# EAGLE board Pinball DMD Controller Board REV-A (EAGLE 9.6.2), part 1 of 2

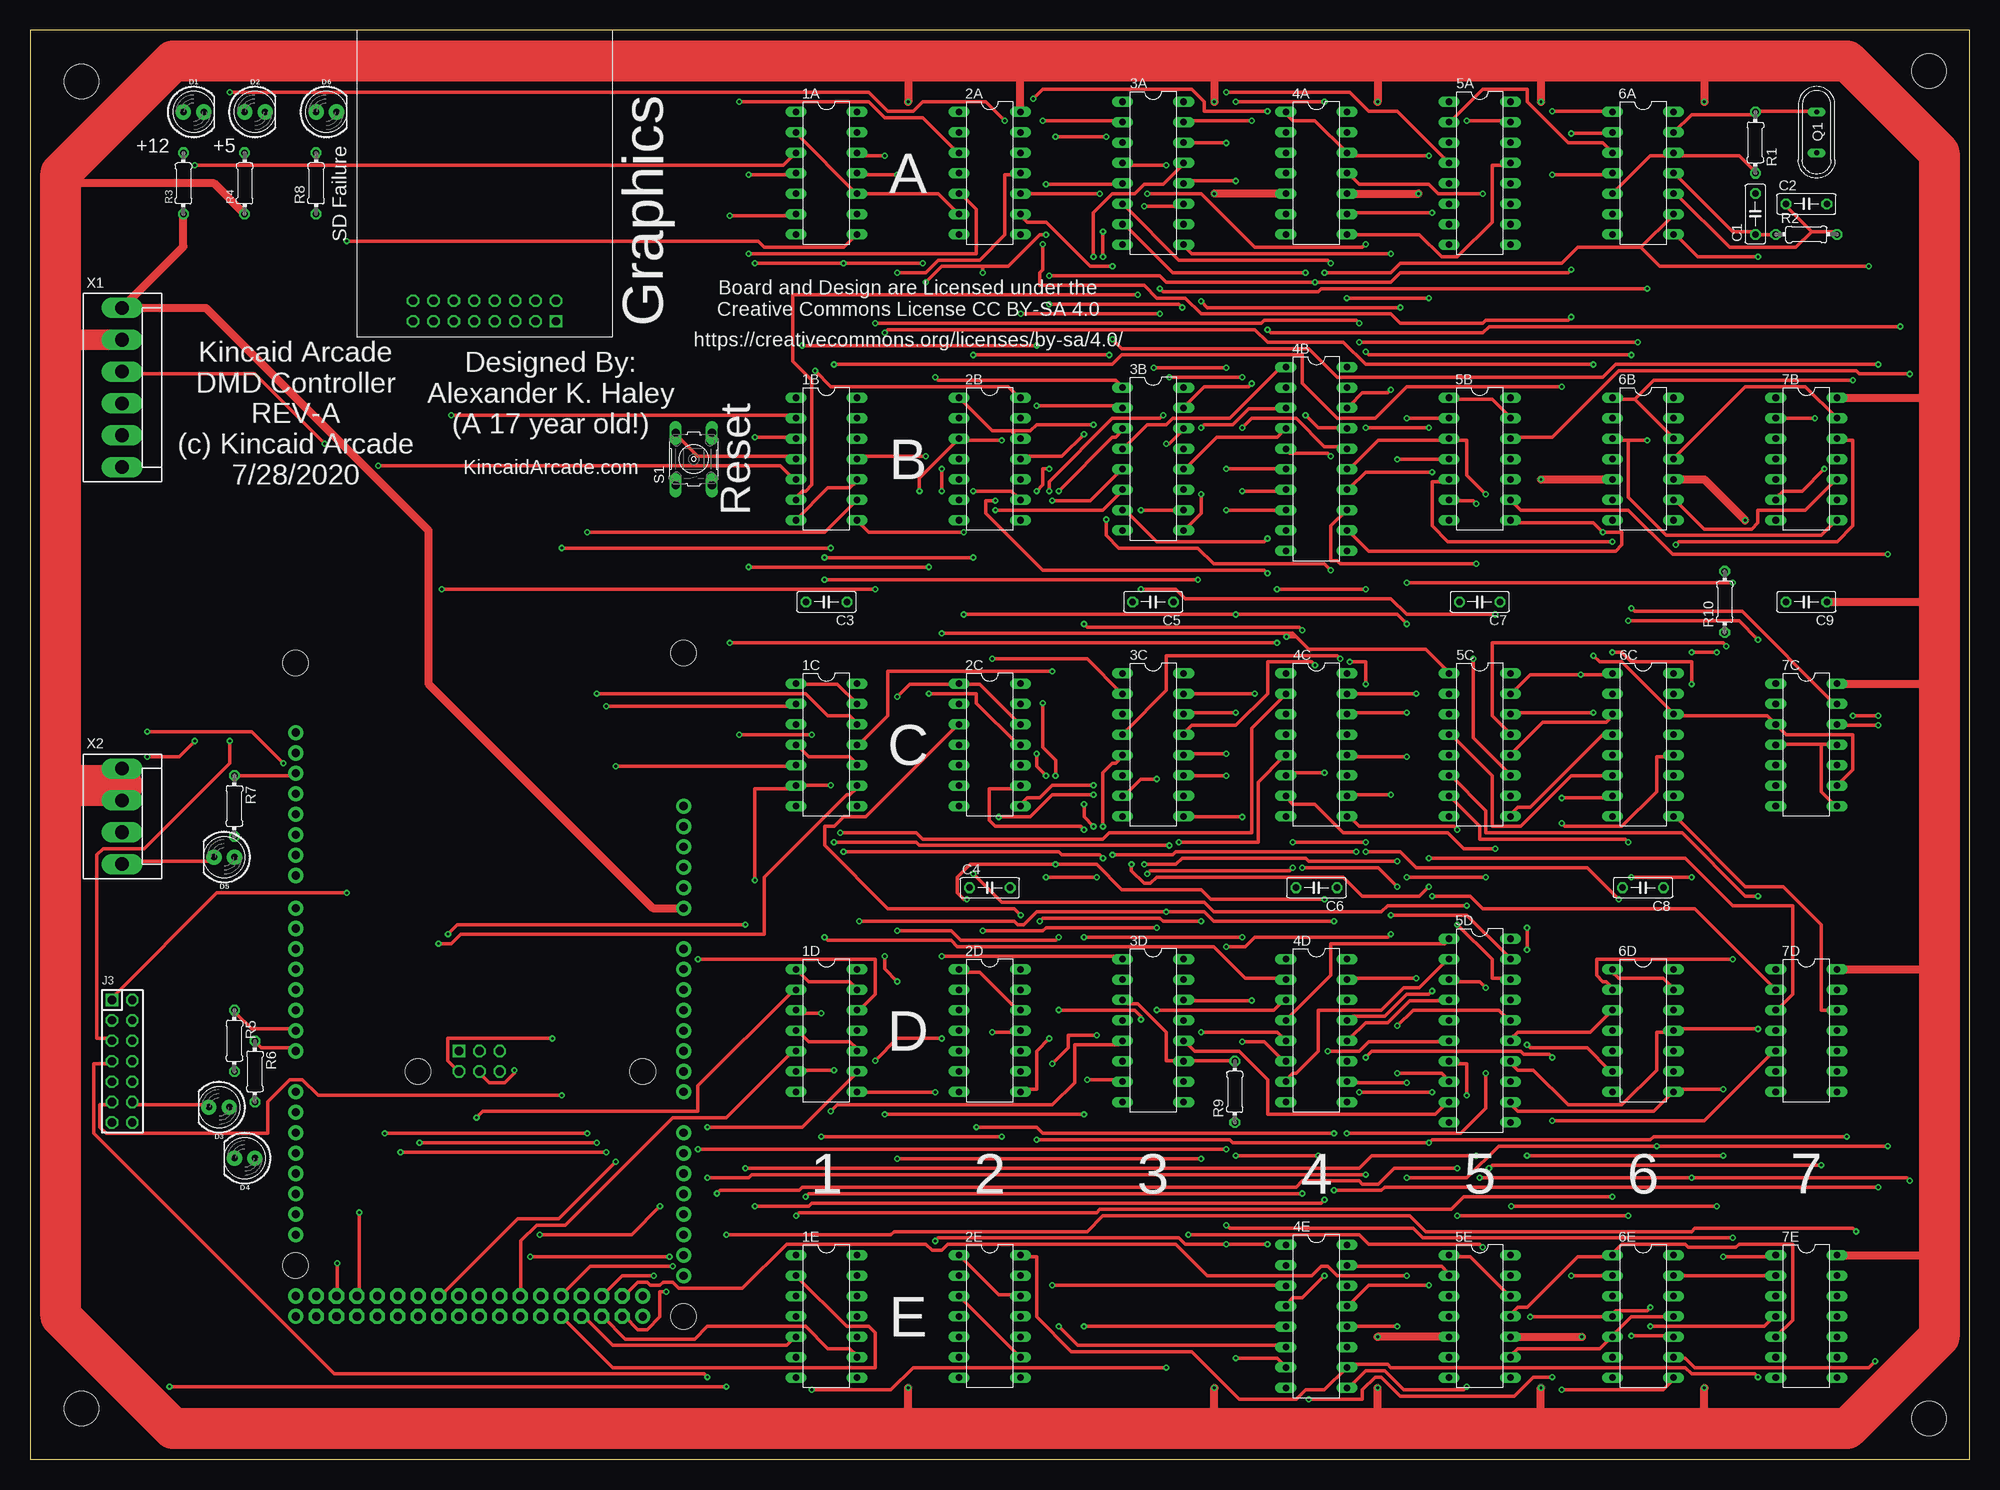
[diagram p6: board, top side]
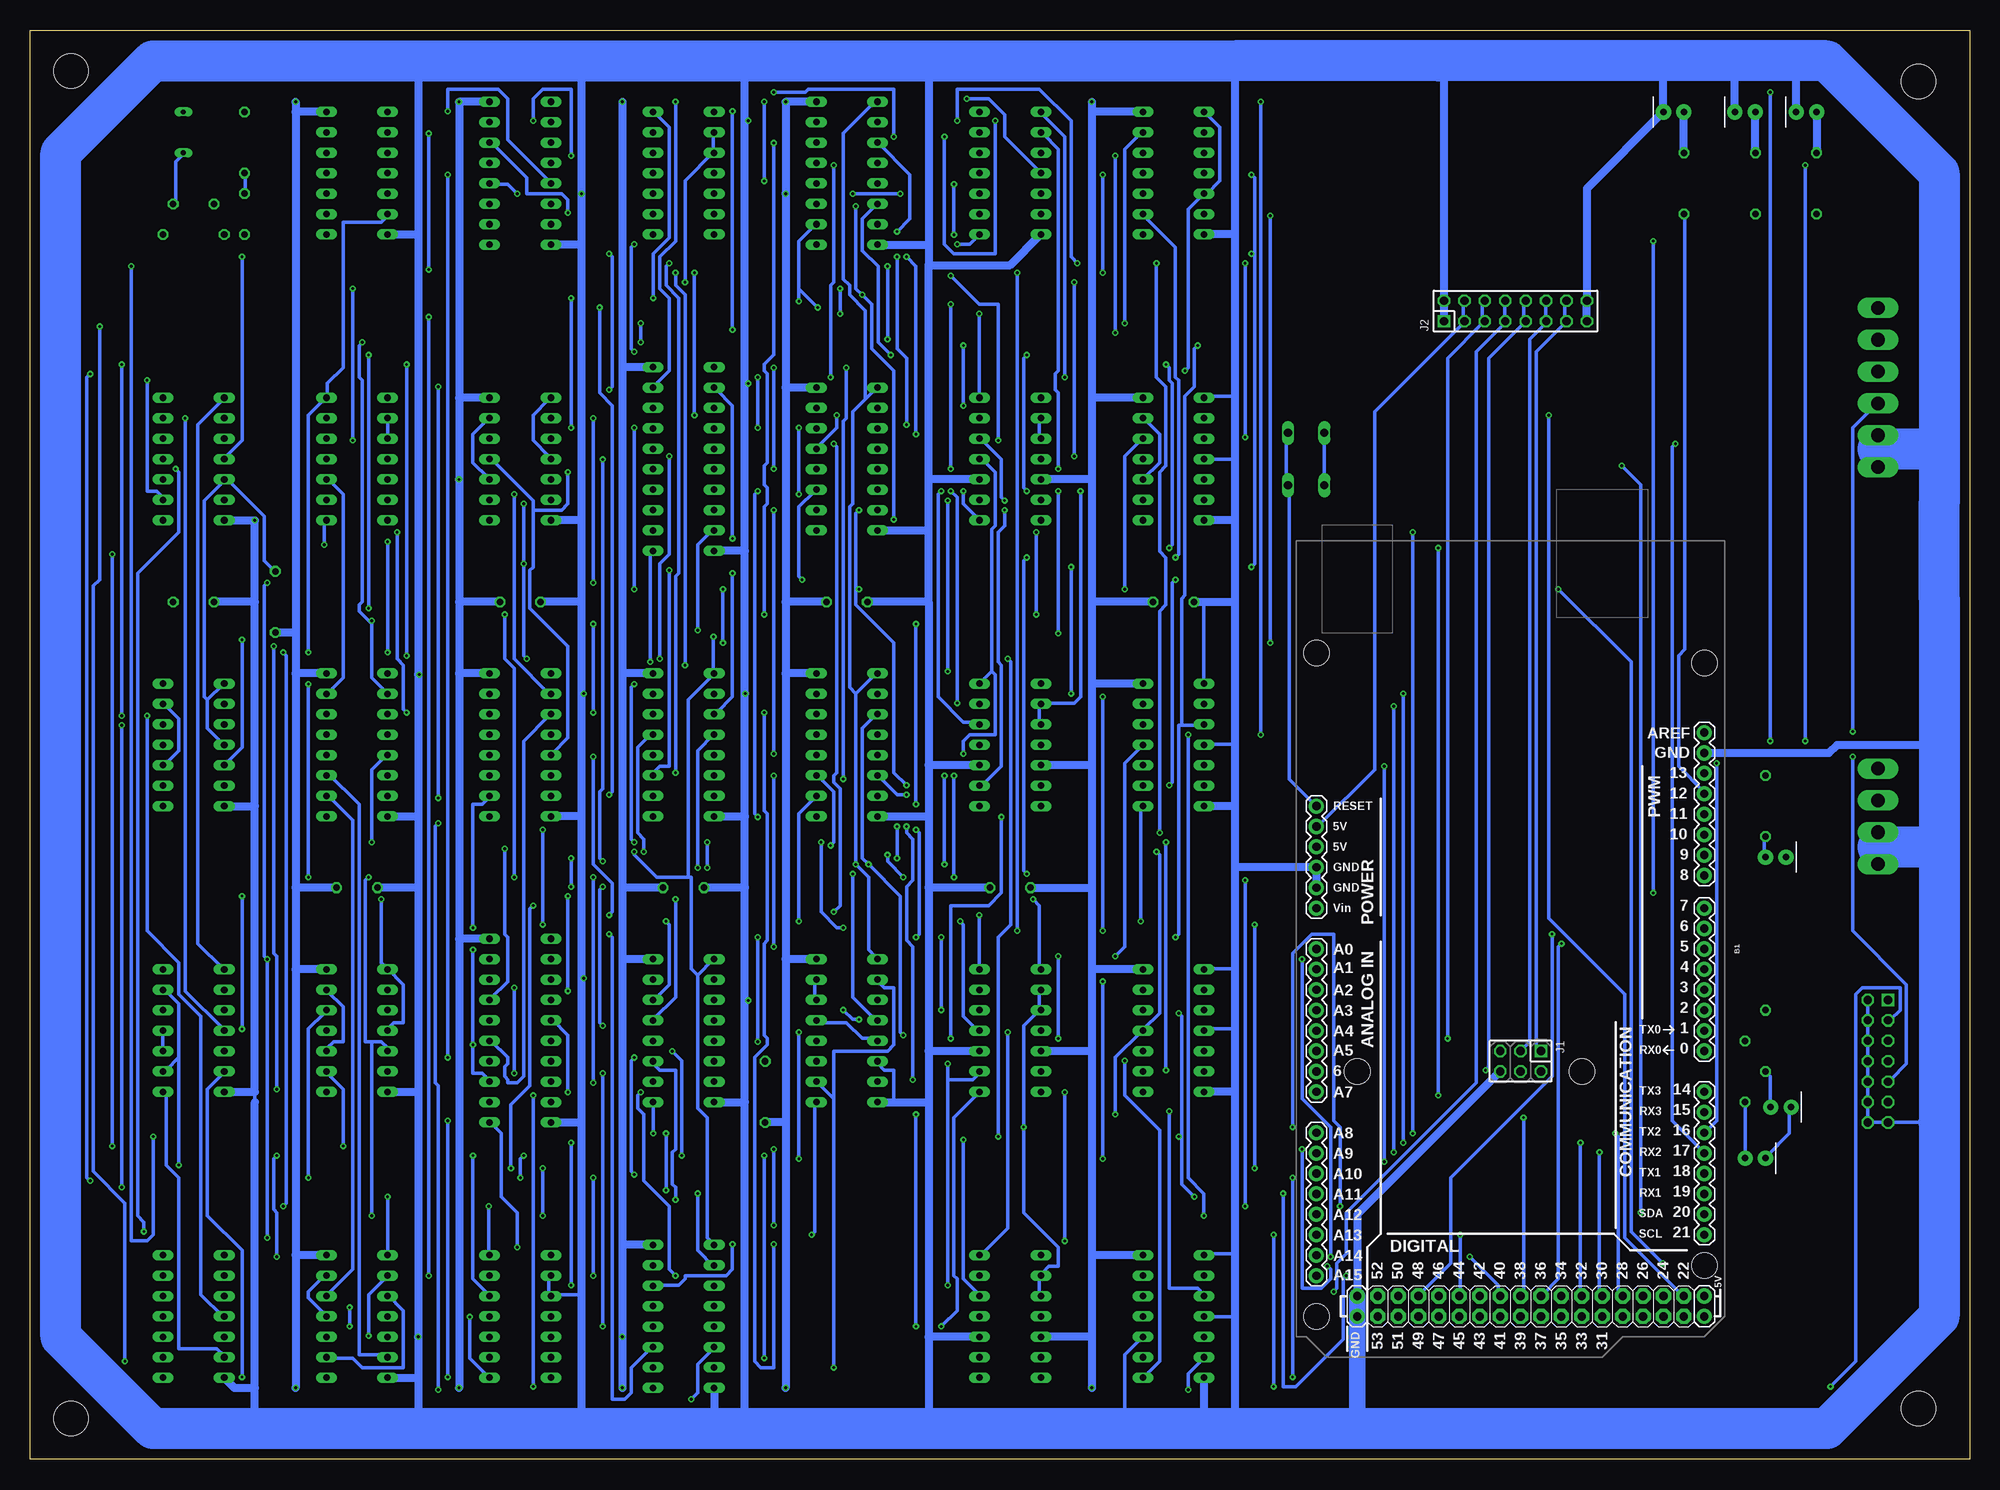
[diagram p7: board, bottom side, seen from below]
Size 241.28 x 177.79 mm. Coordinates in mm from the lower left corner, seen from the top.
Outline: 0,0 241.28,0 241.28,177.79 0,177.79 0,0
Copper layers (1*16): Top 0.035mm / dielectric 1.5mm / Bottom 0.035mm
Design rules "default": minimum track width 6mil, minimum drill 0.35mm, track to track 6mil, track to pad 6mil, pad to pad 6mil, via to via 6mil, smd to smd 6mil, copper to edge 40mil, drill to drill 6mil, minimum pad ring 10mil, minimum via ring 8mil, stop-mask expansion 4mil, vias tented up to drill 0mil, thermal gap 10mil
Net classes: 0 default: width 0.406 mm, clearance 0.381 mm
Holes 4.32 mm at 6.35,6.35 6.35,171.45 236.22,172.72 236.22,5.08

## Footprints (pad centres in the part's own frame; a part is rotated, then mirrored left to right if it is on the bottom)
DIL14 = drill 0.813 long: 1 -7.62,-3.81; 2 -5.08,-3.81; 3 -2.54,-3.81; 4 0,-3.81; 5 2.54,-3.81; 6 5.08,-3.81; 7 7.62,-3.81; 8 7.62,3.81; 9 5.08,3.81; 10 2.54,3.81; 11 0,3.81; 12 -2.54,3.81; 13 -5.08,3.81; 14 -7.62,3.81
DIL16 = drill 0.813 long: 1 -8.89,-3.81; 2 -6.35,-3.81; 3 -3.81,-3.81; 4 -1.27,-3.81; 5 1.27,-3.81; 6 3.81,-3.81; 7 6.35,-3.81; 8 8.89,-3.81; 9 8.89,3.81; 10 6.35,3.81; 11 3.81,3.81; 12 1.27,3.81; 13 -1.27,3.81; 14 -3.81,3.81; 15 -6.35,3.81; 16 -8.89,3.81
DIL20 = drill 0.813 long: 1 -11.43,-3.81; 2 -8.89,-3.81; 3 -6.35,-3.81; 4 -3.81,-3.81; 5 -1.27,-3.81; 6 1.27,-3.81; 7 3.81,-3.81; 8 6.35,-3.81; 9 8.89,-3.81; 10 11.43,-3.81; 11 11.43,3.81; 12 8.89,3.81; 13 6.35,3.81; 14 3.81,3.81; 15 1.27,3.81; 16 -1.27,3.81; 17 -3.81,3.81; 18 -6.35,3.81; 19 -8.89,3.81; 20 -11.43,3.81
ARDUINO_MEGA = drill 1.016 pad 1.88: 0 13.97,24.13; 1 11.43,24.13; 2 8.89,24.13; 3 6.35,24.13; 3.3V -13.97,-24.13; 4 3.81,24.13; 5 1.27,24.13; 5V@0 -11.43,-24.13; 5V@1 44.45,24.13; 5V@2 46.99,24.13; 6 -1.27,24.13; 7 -3.81,24.13; 8 -7.874,24.13; 9 -10.414,24.13; 10 -12.954,24.13; 11 -15.494,24.13; 12 -18.034,24.13; 13 -20.574,24.13; 14 19.05,24.13; 15 21.59,24.13; 16 24.13,24.13; 17 26.67,24.13; 18 29.21,24.13; 19 31.75,24.13; 20 34.29,24.13; 21 36.83,24.13; A0 1.27,-24.13; A1 3.81,-24.13; A2 6.35,-24.13; A3 8.89,-24.13; A4 11.43,-24.13; A5 13.97,-24.13; A6 16.51,-24.13; A7 19.05,-24.13; A8 24.13,-24.13; A9 26.67,-24.13; A10 29.21,-24.13; A11 31.75,-24.13; A12 34.29,-24.13; A13 36.83,-24.13; A14 39.37,-24.13; A15 41.91,-24.13; AREF -25.654,24.13; GND@0 -8.89,-24.13; GND@1 -6.35,-24.13; GND@2 44.45,-19.05; GND@3 46.99,-19.05; GND@4 -23.114,24.13; RESET -16.51,-24.13; VIN -3.81,-24.13 | drill 1.016 pad 1.88 octagon: 22 44.45,21.59; 23 46.99,21.59; 24 44.45,19.05; 25 46.99,19.05; 26 44.45,16.51; 27 46.99,16.51; 28 44.45,13.97; 29 46.99,13.97; 30 44.45,11.43; 31 46.99,11.43; 32 44.45,8.89; 33 46.99,8.89; 34 44.45,6.35; 35 46.99,6.35; 36 44.45,3.81; 37 46.99,3.81; 38 44.45,1.27; 39 46.99,1.27; 40 44.45,-1.27; 41 46.99,-1.27; 42 44.45,-3.81; 43 46.99,-3.81; 44 44.45,-6.35; 45 46.99,-6.35; 46 44.45,-8.89; 47 46.99,-8.89; 48 44.45,-11.43; 49 46.99,-11.43; 50 44.45,-13.97; 51 46.99,-13.97; 52 44.45,-16.51; 53 46.99,-16.51 | hole 3.2: -34.29,24.13; -35.56,-24.13; 16.51,8.89; 16.51,-19.05; 40.64,24.13; 46.99,-24.13
C050-025X075 = drill 0.813 octagon: 1 -2.54,0; 2 2.54,0
LED_5MM = drill 0.813 pad 1.88: A -1.27,0; K 1.27,0
DIL-100-2X03 = drill 1.016 square: 1 -2.54,-1.27 | drill 1.016 octagon: 2 -2.54,1.27; 3 0,-1.27; 4 0,1.27; 5 2.54,-1.27; 6 2.54,1.27
DIL-100-2X08 = drill 1.016 square: 1 -8.89,-1.27 | drill 1.016 octagon: 2 -8.89,1.27; 3 -6.35,-1.27; 4 -6.35,1.27; 5 -3.81,-1.27; 6 -3.81,1.27; 7 -1.27,-1.27; 8 -1.27,1.27; 9 1.27,-1.27; 10 1.27,1.27; 11 3.81,-1.27; 12 3.81,1.27; 13 6.35,-1.27; 14 6.35,1.27; 15 8.89,-1.27; 16 8.89,1.27
DIL-100-2X07 = drill 1.016 square: 1 -7.62,-1.27 | drill 1.016 octagon: 2 -7.62,1.27; 3 -5.08,-1.27; 4 -5.08,1.27; 5 -2.54,-1.27; 6 -2.54,1.27; 7 0,-1.27; 8 0,1.27; 9 2.54,-1.27; 10 2.54,1.27; 11 5.08,-1.27; 12 5.08,1.27; 13 7.62,-1.27; 14 7.62,1.27
QS = drill 0.61 long: 1 -2.54,0; 2 2.54,0
0204/7 = drill 0.813 octagon: 1 -3.81,0; 2 3.81,0
B3F-10XX = drill 1.016 long: 1 -3.251,2.261; 2 3.251,2.261; 3 -3.251,-2.261; 4 3.251,-2.261
KK-156-6 = drill 1.7 pad 2.184 long: 1 -9.9,0; 2 -5.94,0; 3 -1.98,0; 4 1.98,0; 5 5.94,0; 6 9.9,0
KK-156-4 = drill 1.7 pad 2.184 long: 1 -5.94,0; 2 -1.98,0; 3 1.98,0; 4 5.94,0

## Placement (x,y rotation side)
1A  74S08N  [DIL14]  99.06,160.02 270 top
1B  74ACT125N  [DIL14]  99.06,124.46 270 top
1C  74ACT125N  [DIL14]  99.06,88.9 270 top
1D  74ACT125N  [DIL14]  99.06,53.34 270 top
1E  74ACT125N  [DIL14]  99.06,17.78 270 top
2A  7404N  [DIL14]  119.38,160.02 270 top
2B  74LS93N  [DIL14]  119.38,124.46 270 top
2C  74LS93N  [DIL14]  119.38,88.9 270 top
2D  74LS93N  [DIL14]  119.38,53.34 270 top
2E  74LS93N  [DIL14]  119.38,17.78 270 top
3A  74157N  [DIL16]  139.7,160.02 270 top
3B  74157N  [DIL16]  139.7,124.46 270 top
3C  74157N  [DIL16]  139.7,88.9 270 top
3D  74157N  [DIL16]  139.7,53.34 270 top
4A  74LS93N  [DIL14]  160.02,160.02 270 top
4B  7C168A-15PC  [DIL20]  160.02,124.46 270 top
4C  74157N  [DIL16]  160.02,88.9 270 top
4D  74157N  [DIL16]  160.02,53.34 270 top
4E  74157N  [DIL16]  160.02,17.78 270 top
5A  74LS42N  [DIL16]  180.34,160.02 270 top
5B  74125N  [DIL14]  180.34,124.46 270 top
5C  74157N  [DIL16]  180.34,88.9 270 top
5D  7C168A-15PC  [DIL20]  180.34,53.34 270 top
5E  74LS93N  [DIL14]  180.34,17.78 270 top
6A  7404N  [DIL14]  200.66,160.02 270 top
6B  74LS93N  [DIL14]  200.66,124.46 270 top
6C  74S153N  [DIL16]  200.66,88.9 270 top
6D  74125N  [DIL14]  200.66,53.34 270 top
6E  74S11N  [DIL14]  200.66,17.78 270 top
7B  74LS21N  [DIL14]  220.98,124.46 270 top
7C  74107N  [DIL14]  220.98,88.9 270 top
7D  7402N  [DIL14]  220.98,53.34 270 top
7E  74LS21N  [DIL14]  220.98,17.78 270 top
B1  ARDUINO_MEGA_R3FULL  [ARDUINO_MEGA]  57.15,64.77 270 bottom
C1  .1uf  [C050-025X075]  214.63,154.94 90 top
C2  100pf  [C050-025X075]  220.98,156.21 0 top
C3  .1uf  [C050-025X075]  99.06,106.68 180 top
C4  .1uf  [C050-025X075]  119.38,71.12 0 top
C5  .1uf  [C050-025X075]  139.7,106.68 180 top
C6  .1uf  [C050-025X075]  160.02,71.12 180 top
C7  .1uf  [C050-025X075]  180.34,106.68 180 top
C8  .1uf  [C050-025X075]  200.66,71.12 180 top
C9  .1uf  [C050-025X075]  220.98,106.68 180 top
D1  [LED_5MM]  20.32,167.64 0 top
D2  [LED_5MM]  27.94,167.64 0 top
D3  [LED_5MM]  23.5,43.81 180 top
D4  [LED_5MM]  26.67,37.47 180 top
D5  [LED_5MM]  24.13,74.93 180 top
D6  [LED_5MM]  36.83,167.64 0 top
J1  F-2X03-DIL-100  [DIL-100-2X03]  55.88,49.53 180 bottom
J2  F-2X08-DIL-100  [DIL-100-2X08]  56.52,142.88 0 bottom
J3  F-2X07-DIL-100  [DIL-100-2X07]  11.43,49.53 270 top
Q1  12MHZ  [QS]  222.25,165.1 270 top
R1  330  [0204/7]  214.63,163.83 270 top
R2  330  [0204/7]  220.98,152.4 0 top
R3  510  [0204/7]  19.05,158.75 90 top
R4  150  [0204/7]  26.67,158.75 90 top
R5  56  [0204/7]  25.4,52.07 270 top
R6  56  [0204/7]  27.94,48.26 270 top
R7  56  [0204/7]  25.4,81.28 270 top
R8  56  [0204/7]  35.56,158.75 90 top
R9  1K  [0204/7]  149.86,45.72 90 top
R10  1K  [0204/7]  210.82,106.68 90 top
S1  [B3F-10XX]  82.55,124.46 90 top
X1  Connector to Main Board  [KK-156-6]  11.43,133.35 270 top
X2  DMD-POWER  [KK-156-4]  11.43,80.01 270 top

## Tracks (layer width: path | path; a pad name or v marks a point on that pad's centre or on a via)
1H  (via drill 0.35)
  Top 0.406: v153.94,110.24 153.54,110.63 125.98,110.63 118.9,117.72 118.9,119.29 v120.08,119.29 | 122.05,127.95 119.69,127.95 115.75,131.89 2B.1 | 122.05,127.95 122.83,127.17 2B.12 | v133.46,149.61 v133.46,152.76 | v132.28,128.74 125.2,128.74 124.41,127.95 122.05,127.95
  Bottom 0.406: v153.94,110.24 153.94,94.88 155.91,92.91 4C.3 | v120.08,119.29 120.47,119.69 120.47,124.41 122.83,126.77 2B.12 | v133.46,152.76 131.89,154.33 131.89,159.84 135.83,163.78 3A.3 | v133.46,149.61 133.46,138.19 132.28,137.01 v132.28,128.74
1V  (via drill 0.35)
  Top 0.406: 2D.12 122.83,55.91 118.11,60.63 115.75,60.63 2D.1 | v140.94,129.92 140.55,129.53 134.65,129.53 126.77,121.65 v126.77,120.47 | v125.98,94.09 125.98,88.58 127.56,87.01 v127.56,85.04 | v116.53,69.69 116.14,69.69 115.35,70.47 115.35,72.44 116.93,74.02 v127.56,74.02 132.68,74.02 135.83,70.87 145.67,70.87 146.85,69.69 v161.02,69.69 | 7D.2 207.09,68.5 180.71,68.5 179.13,70.08 v174.41,70.08 | v174.41,58.27 174.01,57.87 171.26,57.87 168.5,55.12 164.57,55.12 164.17,54.72 4D.13
  Bottom 0.406: v140.94,129.92 140.94,128.35 143.31,125.98 3B.13 | v126.77,120.47 125.98,119.69 v125.98,94.09 | v127.56,74.02 v127.56,85.04 | v116.53,69.69 115.75,68.9 115.75,61.02 2D.1 | v161.02,69.69 161.02,57.48 163.78,54.72 4D.13 | v174.41,58.27 v174.41,70.08
2H  (via drill 0.35)
  Top 0.406: v161.02,85.43 156.3,85.43 4C.6 | v161.81,148.82 161.42,149.21 142.91,149.21 136.22,155.91 3A.6 | v117.32,120.47 122.05,120.47 122.83,119.69 2B.9 | v134.25,137.4 v117.32,137.4
  Bottom 0.406: v161.02,85.43 161.02,109.84 160.63,110.24 160.63,144.49 162.2,146.06 162.2,148.43 v161.81,148.82 | v117.32,120.47 117.72,120.87 117.72,137.01 v117.32,137.4 | v134.25,137.4 135.83,138.98 135.83,148.43 137.79,150.39 137.79,154.33 136.22,155.91 3A.6
2V  (via drill 0.35)
  Top 0.406: v127.17,21.65 155.91,21.65 4E.3 | v174.01,74.8 205.91,74.8 211.81,68.9 219.29,68.9 219.29,57.87 217.32,55.91 7D.3 | v174.01,71.26 172.83,70.08 165.75,70.08 163.39,72.44 140.16,72.44 139.37,71.65 138.58,71.65 137.01,73.23 v137.01,74.02 | v127.17,49.21 129.13,51.18 129.13,52.76 v132.68,52.76
  Bottom 0.406: 127.17,47.24 124.02,47.24 123.23,48.03 2D.9 | v127.17,21.65 127.17,47.24 | v174.01,71.26 v174.01,74.8 | 3C.3 136.22,92.52 137.79,90.94 137.79,74.8 v137.01,74.02 133.07,70.08 133.07,53.15 v132.68,52.76 | v127.17,49.21 127.17,47.24
4H  (via drill 0.35)
  Top 0.406: v125.2,120.47 125.98,121.26 125.98,123.23 v126.77,123.23 | v126.77,143.7 142.91,143.7 v143.31,143.31 | v169.29,82.68 164.17,82.68 4C.10 | v170.47,143.31 146.46,143.31 v145.67,144.09
  Bottom 0.406: v125.2,120.47 125.2,118.9 123.23,116.93 2B.8 | v126.77,143.7 v126.77,123.23 | 145.67,145.67 v143.31,143.31 | 145.67,145.67 145.67,151.57 143.7,153.54 3A.10 | v169.29,82.68 168.9,83.07 168.9,131.1 170.47,132.68 v170.47,143.31 | 145.67,145.67 v145.67,144.09
4V  (via drill 0.35)
  Top 0.406: v127.95,16.54 130.31,14.17 155.91,14.17 4E.6 | v132.28,82.68 127.17,82.68 124.41,79.92 v120.47,79.92 | v126.77,52.36 125.2,50.79 125.2,46.06 123.23,46.06 2D.8 | v189.37,42.13 208.27,42.13 216.93,50.79 7D.5 | v189.37,10.24 187.01,10.24 184.65,7.87 170.47,7.87 168.11,10.24 167.32,10.24 165.75,8.66 165.75,7.48 v159.06,7.48
  Bottom 0.406: v127.95,16.54 125.98,18.5 125.98,22.44 126.38,22.84 126.38,42.52 123.23,45.67 2D.8 | v132.28,82.68 133.46,82.68 135.83,85.04 3C.6 | v120.47,79.92 120.47,70.47 122.05,68.9 126.77,68.9 v126.77,52.36 | v189.37,10.24 v189.37,42.13 | v159.06,7.48 158.27,8.27 158.27,11.81 156.3,13.78 4E.6
8H  (via drill 0.35)
  Top 0.406: v132.28,149.61 132.28,155.12 134.65,157.48 137.4,157.48 138.58,158.66 140.94,158.66 143.31,161.02 3A.13 | v131.1,127.56 128.35,124.8 123.23,124.8 2B.11 | v164.96,75.59 142.52,75.59 142.13,75.2 v134.65,75.2 | v126.38,72.44 v132.68,72.44 | v126.38,85.04 125.2,86.22 v125.2,87.8
  Bottom 0.406: 121.65,98.03 122.83,96.85 2C.14 | 121.65,98.03 121.65,115.75 121.26,116.14 121.26,122.83 122.83,124.41 2B.11 | v132.28,149.61 131.1,148.43 v131.1,127.56 | v164.96,75.59 164.96,77.17 165.75,77.95 165.75,88.58 164.17,90.16 4C.13 | v134.65,75.2 134.65,74.41 v132.68,72.44 | v126.38,85.04 v126.38,72.44 | v125.2,87.8 125.2,89.37 124.41,90.16 121.26,90.16 121.26,97.64 121.65,98.03
8V  (via drill 0.35)
  Top 0.406: 2E.14 123.23,25.2 125.2,25.2 125.2,17.72 129.53,13.39 144.49,13.39 150.39,7.48 157.48,7.48 158.66,8.66 161.02,8.66 163.78,11.42 4E.10 164.17,11.81 168.9,11.81 169.29,11.42 205.91,11.42 206.69,10.63 214.57,10.63 v214.96,10.24 | v119.69,53.15 122.83,53.15 2D.11 | v145.67,66.93 140.94,66.93 140.55,67.32 125.98,67.32 v125.59,66.93
  Bottom 0.406: v119.69,53.15 119.69,28.74 122.83,25.59 2E.14 | v145.67,66.93 145.67,80.31 143.7,82.28 3C.10 | v125.59,66.93 125.2,66.53 125.2,55.12 123.23,53.15 2D.11 | v214.96,10.24 214.96,25.98 219.29,30.32 219.29,46.06 217.32,48.03 7D.6
12MHZ  (via drill 0.35)
  Top 0.406: v209.84,31.5 v184.25,31.5 | v206.69,100.39 v209.84,100.39
  Bottom 0.406: v184.25,31.5 184.25,25.59 5E.14 | v209.84,31.5 209.45,31.89 209.45,100 v209.84,100.39 | v206.69,100.39 206.69,129.92 204.72,131.89 6B.14 204.33,132.28 204.33,133.86 202.36,135.83 202.36,153.94 197.64,153.94 196.85,154.72 6A.6
16H  (via drill 0.35)
  Top 0.406: 2C.12 122.83,91.73 118.11,96.46 115.75,96.46 2C.1 115.35,96.46 109.45,96.46 v107.87,94.88 | v127.95,120.47 134.65,127.17 135.04,127.17 135.83,127.95 3B.3 | v140.16,55.91 154.72,55.91 155.91,57.09 4D.3 | v138.19,54.72 138.19,55.12 137.4,55.91 v127.95,55.91 | v127.95,64.96 127.56,64.57 115.75,64.57 114.57,65.75 v107.87,65.75
  Bottom 0.406: v127.95,120.47 128.35,120.08 128.35,94.88 125.2,91.73 123.23,91.73 2C.12 | v140.16,55.91 138.98,54.72 v138.19,54.72 | v127.95,64.96 v127.95,55.91 | v107.87,94.88 v107.87,65.75
16V  (via drill 0.35)
  Top 0.406: 2E.1 115.75,25.2 120.47,20.47 122.83,20.47 2E.12 | v174.01,21.65 166.53,21.65 164.17,19.29 4E.13 | v125.2,39.76 149.21,39.76 149.61,39.37 v174.01,39.37 174.41,39.76 201.57,39.76 201.97,40.16 v225.98,40.16 | v159.84,98.82 159.45,99.21 153.94,99.21 153.94,95.28 150,91.34 144.49,91.34 143.7,90.55 3C.13 | v161.02,147.64 169.29,147.64 170.47,148.82 190.55,148.82 192.52,150.79 200.39,150.79 | 200.39,150.79 204.33,154.72 6A.9 | v228.74,148.43 202.76,148.43 200.39,150.79
  Bottom 0.406: v174.01,39.37 v174.01,21.65 | v125.2,39.76 125.2,22.44 123.23,20.47 2E.12 | v159.84,98.82 159.84,144.88 161.02,146.06 v161.02,147.64 | v225.98,40.16 225.98,27.95 226.77,27.16 228.74,27.16 v228.74,148.43
32H  (via drill 0.35)
  Top 0.406: v120.08,118.11 133.46,118.11 135.83,120.47 3B.6 | v150.79,51.97 153.54,51.97 155.91,49.61 4D.6 | v131.1,64.96 v150.79,64.96 | v131.1,78.35 130.71,78.74 120.08,78.74 119.29,79.53 119.29,83.46 122.83,83.46 2C.9
  Bottom 0.406: v120.08,118.11 120.08,116.14 120.87,115.35 120.87,99.21 120.47,98.82 120.47,86.22 122.83,83.86 2C.9 | v150.79,64.96 v150.79,51.97 | v131.1,64.96 130.71,65.35 130.71,77.95 v131.1,78.35
32V  (via drill 0.35)
  Top 0.406: 2E.9 122.83,12.99 115.75,20.08 2E.3 | v229.92,91.34 224.8,91.34 7C.12 | v229.92,33.86 168.5,33.86 168.11,33.47 v162.2,33.47 | v162.2,40.55 125.98,40.55 125.2,41.34 v117.72,41.34
  Bottom 0.406: 2E.3 115.75,20.47 115.75,22.84 2E.2 115.35,23.23 114.57,24.02 113.39,24.02 113.39,26.38 117.72,30.71 v117.72,41.34 117.72,53.94 115.75,55.91 | 115.75,55.91 115.75,58.27 2D.2 | v229.92,33.86 v229.92,91.34 | v162.2,40.55 v162.2,33.47 | 115.75,55.91 2D.3
64H  (via drill 0.35)
  Top 0.406: v132.28,83.86 127.17,83.86 125.59,82.28 124.02,82.28 123.23,81.5 2C.8 | 3B.10 v138.19,118.11 | v171.26,46.85 164.17,46.85 4D.10 | v181.1,72.44 v171.26,72.44 | v182.28,105.12 171.26,105.12 169.29,107.09 143.7,107.09 142.52,108.27 v138.19,108.27
  Bottom 0.406: v132.28,83.86 133.86,85.43 133.86,101.58 138.58,106.3 138.58,108.27 | 138.58,108.27 138.58,117.72 v138.19,118.11 | v171.26,72.44 v171.26,46.85 | v181.1,72.44 181.1,98.42 182.28,99.61 v182.28,105.12 | 138.58,108.27 v138.19,108.27
128H  (via drill 0.35)
  Top 0.406: v111.81,95.28 117.72,95.28 117.72,94.09 122.83,88.98 2C.11 | v89.37,111.02 v111.81,111.02 | v89.37,159.84 94.88,159.84 1A.4 | v89.37,150 117.72,150 117.72,155.51 115.75,157.48 2A.5
  Bottom 0.406: v111.81,111.02 v111.81,95.28 | v89.37,111.02 88.98,111.42 88.98,150 | 88.98,150 88.98,159.45 v89.37,159.84 | 88.98,150 v89.37,150
+12VDC
  Top 1.016: R3.1 19.05,150.87 X1.1 21.85,143.25 49.53,115.57 49.53,96.52 77.47,68.58 B1.VIN
/128H
  Top 0.406: 2A.6 115.35,155.12 112.99,157.48 1A.10 102.76,157.48 95.28,164.96 1A.2
/LSWHICHBUFFER  (via drill 0.35)
  Top 0.406: 6D.1 196.85,60.63 197.64,59.84 203.15,59.84 204.33,58.66 6D.13 | v197.64,69.69 193.7,73.62 172.44,73.62 170.47,75.59 v166.14,75.59 | v113.39,120.47 v113.39,123.23 | v113.39,102.76 157.09,102.76 157.48,102.36 | 157.48,102.36 159.06,100.79 173.62,100.79 176.38,98.03 5C.1 | 157.48,102.36 v156.3,102.36
  Bottom 0.406: 196.85,61.02 194.88,59.05 194.88,54.33 196.06,54.33 196.85,53.54 6D.4 | 6D.10 204.33,51.18 203.54,51.97 202.36,51.97 202.36,56.3 204.33,58.27 6D.13 | 158.27,60.24 158.27,43.7 157.09,42.52 157.09,27.56 156.3,26.77 4E.1 | 158.27,60.24 156.3,62.2 4D.1 | 196.85,61.02 197.64,61.81 v197.64,69.69 | v166.14,75.59 166.14,75.2 163.39,72.44 159.45,72.44 | 159.45,72.44 159.06,72.44 159.06,61.02 158.27,60.24 | 196.85,61.02 6D.1 | v113.39,123.23 113.39,132.68 113.78,133.07 113.78,135.04 113.39,135.43 113.39,162.99 115.35,164.96 2A.2 | v113.39,102.76 v113.39,120.47 | v156.3,102.36 156.3,98.03 4C.1 156.3,97.64 159.45,94.49 159.45,72.44
/PWMCOUNTERC  (via drill 0.35)
  Top 0.406: v199.21,15.35 204.33,15.35 6E.10 | v125.98,151.18 125.98,148.03 125.59,147.64 125.59,146.06 138.58,146.06 140.16,144.49 143.7,144.49 145.67,142.52 169.29,142.52 170.47,141.34 180.71,141.34 181.1,141.73 191.34,141.73 v191.73,142.13 | v191.73,22.84 196.85,22.84 6E.2
  Bottom 0.406: v199.21,15.35 199.21,20.47 196.85,22.84 6E.2 | 2A.8 124.41,151.18 v125.98,151.18 | v191.73,22.84 v191.73,142.13
/PWMCOUNTERD  (via drill 0.35)
  Top 0.406: v124.8,169.29 125.98,170.47 144.49,170.47 146.06,168.9 146.06,167.72 v153.94,167.72 | v153.94,140.55 154.33,140.16 180.71,140.16 181.5,140.94 v232.68,140.94 | v229.53,12.21 228.74,11.42 207.09,11.42 205.91,12.6 204.72,12.6 6E.9
  Bottom 0.406: 6E.9 204.33,12.6 201.18,12.6 200,11.42 194.88,11.42 194.88,18.5 196.85,20.47 6E.3 | v124.8,169.29 122.05,169.29 120.08,167.32 120.08,164.57 115.75,160.24 2A.4 | v153.94,140.55 v153.94,167.72 | v232.68,140.94 232.68,109.45 233.46,108.66 233.46,35.83 229.53,31.89 v229.53,12.21
A0  (via drill 0.35)
  Top 0.406: v52.36,129.92 94.88,129.92 1B.2
  Bottom 0.406: v52.36,129.92 52.36,67.32 42.91,57.87 42.91,27.56 35.83,20.47 B1.22
A1  (via drill 0.35)
  Top 0.406: v51.18,108.27 v105.12,108.27 | v38.19,24.41 38.19,20.47 B1.24
  Bottom 0.406: v105.12,108.27 105.12,124.8 103.15,126.77 1B.12 | v51.18,108.27 42.13,99.21 42.13,28.35 v38.19,24.41
A2  (via drill 0.35)
  Top 0.406: v43.31,123.62 93.31,123.62 94.88,122.05 1B.5 | v40.95,30.71 40.95,20.47 B1.26
  Bottom 0.406: v43.31,123.62 40.95,121.26 v40.95,30.71
A3  (via drill 0.35)
  Top 0.406: v69.29,115.35 98.82,115.35 102.76,119.29 1B.9 | v44.09,40.55 v69.29,40.55
  Bottom 0.406: v69.29,40.55 v69.29,115.35 | v44.09,40.55 43.7,40.16 43.7,20.87 43.31,20.47 B1.28
A4  (via drill 0.35)
  Top 0.406: v71.65,93.7 94.88,93.7 1C.2 | v46.06,38.19 v71.65,38.19
  Bottom 0.406: v71.65,38.19 v71.65,93.7 | v46.06,38.19 46.06,20.47 B1.30
A5  (via drill 0.35)
  Top 0.406: v70.47,95.28 96.46,95.28 99.21,92.52 101.97,92.52 102.76,91.73 1C.12 | v48.42,39.37 v70.47,39.37
  Bottom 0.406: v70.47,39.37 v70.47,95.28 | v48.42,39.37 48.42,20.47 B1.32
A6  (via drill 0.35)
  Top 0.406: v72.83,86.22 94.88,86.22 1C.5 | v72.83,37.01 65.75,29.92 60.63,29.92 51.18,20.47 B1.34
  Bottom 0.406: v72.83,37.01 v72.83,86.22
A7  (via drill 0.35)
  Top 0.406: v50.79,64.17 52.36,64.17 53.54,65.35 91.34,65.35 91.34,72.44 101.58,82.68 101.97,82.68 102.76,83.46 1C.9
  Bottom 0.406: v50.79,64.17 51.18,63.78 51.18,22.44 53.15,20.47 B1.36
A8  (via drill 0.35)
  Top 0.406: v55.51,42.52 56.3,43.31 83.07,43.31 83.07,46.46 94.88,58.27 1D.2
  Bottom 0.406: v55.51,42.52 55.51,20.47 B1.38
A9  (via drill 0.35)
  Top 0.406: v83.07,62.2 105.12,62.2 105.12,57.87 103.15,55.91 1D.12 | v62.2,25.2 v79.53,25.2
  Bottom 0.406: v83.07,62.2 83.07,44.88 79.53,41.34 v79.53,25.2 | v62.2,25.2 58.66,21.65 58.66,20.47 B1.40
A10
  Top 0.406: 1D.5 94.88,50.79 86.61,42.52 79.92,42.52 66.53,29.13 62.99,29.13 61.02,27.16 61.02,20.47 B1.42
A11  (via drill 0.35)
  Top 0.406: v84.25,41.34 96.06,41.34 102.76,48.03 1D.9 | v78.35,31.5 74.8,27.95 v63.39,27.95
  Bottom 0.406: v84.25,41.34 84.25,62.99 81.89,65.35 79.13,65.35 79.13,42.13 78.35,41.34 v78.35,31.5 | v63.39,27.95 63.39,20.47 B1.44
A_A0  (via drill 0.35)
  Top 0.406: v141.34,161.02 136.22,161.02 3A.4 | v150.79,134.65 v141.73,134.65 | v150.79,128.35 151.97,129.53 157.48,129.53 161.02,125.98 163.78,125.98 4B.16
  Bottom 0.406: v141.34,161.02 141.34,146.46 141.73,146.06 v141.73,134.65 | v150.79,128.35 v150.79,134.65
A_A1  (via drill 0.35)
  Top 0.406: v158.66,147.64 142.13,147.64 136.22,153.54 3A.7 | v158.66,129.92 160.24,128.35 163.78,128.35 4B.17
  Bottom 0.406: v158.66,129.92 v158.66,147.64
A_A2  (via drill 0.35)
  Top 0.406: v169.29,150 144.49,150 143.7,150.79 3A.9 | v169.29,133.07 168.9,132.68 165.75,132.68 164.17,131.1 4B.18
  Bottom 0.406: v169.29,150 168.9,149.61 168.9,133.46 v169.29,133.07
A_A3  (via drill 0.35)
  Top 0.406: v150,168.9 v161.02,168.9 | v150,159.06 143.7,159.06 3A.12
  Bottom 0.406: v161.02,168.9 161.02,151.57 162.99,149.61 162.99,145.67 161.81,144.49 161.81,135.43 163.78,133.46 4B.19 | v150,159.06 v150,168.9
A_A4
  Top 0.406: 3B.4 136.22,125.98 138.98,128.74 141.34,128.74 142.13,129.53 149.21,129.53 155.51,135.83 155.91,135.83 4B.1
A_A5  (via drill 0.35)
  Top 0.406: v153.94,114.57 153.54,114.17 140.16,114.17 136.22,118.11 3B.7
  Bottom 0.406: v153.94,114.57 153.94,131.1 155.91,133.07 4B.2
A_A6  (via drill 0.35)
  Top 0.406: v145.67,120.08 145.67,117.72 143.7,115.75 3B.9 | v145.67,128.35 146.06,128.74 149.61,128.74 151.57,130.71 155.91,130.71 4B.3
  Bottom 0.406: v145.67,128.35 v145.67,120.08
A_A7
  Top 0.406: 3B.12 143.7,123.23 147.64,127.17 155.12,127.17 155.91,127.95 4B.4
A_A8  (via drill 0.35)
  Top 0.406: v162.99,99.61 162.6,100 141.34,100 141.34,95.67 136.22,90.55 3C.4 | v161.81,124.8 161.42,125.2 156.69,125.2 156.3,125.59 4B.5
  Bottom 0.406: v162.99,99.61 162.99,111.42 161.81,112.6 v161.81,124.8
A_A9  (via drill 0.35)
  Top 0.406: v140.16,84.64 138.19,84.64 136.22,82.68 3C.7 | v148.82,135.83 v139.76,135.83 | v148.82,123.23 155.91,123.23 4B.6
  Bottom 0.406: v140.16,84.64 140.16,129.13 139.76,129.53 v139.76,135.83 | v148.82,123.23 v148.82,135.83
A_A10  (via drill 0.35)
  Top 0.406: v150.79,79.92 143.7,79.92 3C.9 | v150.79,120.47 155.91,120.47 4B.7
  Bottom 0.406: v150.79,79.92 151.18,80.31 151.18,120.08 v150.79,120.47
A_A11  (via drill 0.35)
  Top 0.406: v148.82,87.8 143.7,87.8 3C.12 | 4B.8 v148.82,118.11
  Bottom 0.406: v148.82,118.11 v148.82,87.8
B_A0  (via drill 0.35)
  Top 0.406: v170.08,53.94 172.05,55.91 182.68,55.91 183.86,54.72 5D.16 | v170.08,71.26 167.72,73.62 v158.27,73.62
  Bottom 0.406: v170.08,53.94 170.47,54.33 170.47,70.87 v170.08,71.26 | v158.27,73.62 158.27,88.19 156.3,90.16 4C.4
B_A1  (via drill 0.35)
  Top 0.406: v182.28,75.98 178.35,75.98 176.38,77.95 163.39,77.95 159.84,81.5 157.09,81.5 156.3,82.28 4C.7
  Bottom 0.406: v182.28,75.98 182.28,65.35 181.89,64.96 181.89,59.45 183.86,57.48 5D.17
B_A2  (via drill 0.35)
  Top 0.406: v177.56,78.35 177.16,78.74 165.35,78.74 164.17,79.92 4C.9 | v177.56,66.53 181.89,62.2 181.89,59.84 183.86,59.84 5D.18
  Bottom 0.406: v177.56,66.53 v177.56,78.35
B_A3  (via drill 0.35)
  Top 0.406: v171.26,87.4 164.17,87.4 4C.12 | v169.29,67.72 178.74,67.72 183.86,62.6 5D.19
  Bottom 0.406: v171.26,87.4 171.26,74.02 168.9,71.65 168.9,68.11 v169.29,67.72
B_A4
  Top 0.406: 4D.4 156.3,54.72 161.81,60.24 161.81,64.17 175.98,64.17 176.38,64.57 5D.1
B_A5
  Top 0.406: 4D.7 156.3,47.24 157.09,48.03 157.48,48.03 160.24,50.79 160.24,55.91 168.11,55.91 170.87,58.66 172.83,58.66 176.38,62.2 5D.2
B_A6  (via drill 0.35)
  Top 0.406: v163.78,40.55 177.95,40.55 181.1,43.7 v181.1,48.03 | v181.1,58.66 180.31,59.45 176.77,59.45 5D.3
  Bottom 0.406: v163.78,40.55 163.78,44.09 4D.9 | v181.1,58.66 v181.1,48.03
B_A7
  Top 0.406: 4D.12 164.17,52.36 166.14,54.33 168.9,54.33 171.65,57.09 176.38,57.09 5D.4
B_A8  (via drill 0.35)
  Top 0.406: v161.02,22.84 158.27,20.08 157.09,20.08 156.3,19.29 4E.4 | v174.41,45.67 v165.35,45.67
  Bottom 0.406: v161.02,22.84 161.81,23.62 161.81,31.5 164.96,34.65 164.96,42.91 165.75,43.7 165.75,45.28 v165.35,45.67 | v174.41,45.67 174.41,52.76 176.38,54.72 5D.5
B_A9  (via drill 0.35)
  Top 0.406: v150,12.6 155.12,12.6 155.91,11.81 4E.7 | v160.24,37.8 v150,37.8 | v161.42,50.79 165.35,50.79 166.53,51.97 176.38,51.97 5D.6
  Bottom 0.406: v150,37.8 v150,12.6 | v160.24,37.8 160.24,49.61 v161.42,50.79
B_A10  (via drill 0.35)
  Top 0.406: v178.74,9.05 178.35,8.66 170.87,8.66 168.5,11.02 166.14,11.02 164.17,9.05 4E.9 | v178.74,45.28 178.74,49.21 176.77,49.21 5D.7
  Bottom 0.406: v178.74,45.28 v178.74,9.05
B_A11  (via drill 0.35)
  Top 0.406: v170.08,16.54 164.17,16.54 4E.12 | v170.08,48.03 175.59,48.03 176.38,47.24 5D.8
  Bottom 0.406: v170.08,48.03 v170.08,16.54
CEA  (via drill 0.35)
  Top 0.406: v131.5,47.24 135.83,47.24 3D.7 | v132.28,78.74 131.1,79.92 v131.1,81.5 | v131.1,103.94 131.5,103.54 157.87,103.54 v158.27,103.15
  Bottom 0.406: v131.5,47.24 131.5,63.78 132.28,64.57 132.28,71.26 131.5,72.05 131.5,77.17 132.28,77.95 v132.28,78.74 | v131.1,103.94 v131.1,81.5 | v158.27,103.15 158.27,113.78 156.3,115.75 4B.9
CEB
  Top 0.406: 3D.12 143.7,51.97 144.88,50.79 150.39,50.79 153.94,47.24 153.94,42.91 174.8,42.91 175.98,44.09 176.38,44.09 5D.9
CHIPENABLE
  Top 0.406: 1E.2 101.58,16.54 104.33,16.54 105.12,15.75 105.12,11.42 72.44,11.42 66.14,17.72 B1.47
CLK  (via drill 0.35)
  Top 0.406: 198.82,126.77 198.82,119.69 203.54,114.96 222.83,114.96 224.41,116.53 7B.8 | 198.82,126.77 196.85,126.77 6B.3 | v97.64,135.43 99.61,133.46 121.65,133.46 122.83,132.28 2B.14 | v201.18,126.77 198.82,126.77 | v201.18,145.67 160.63,145.67 160.24,145.28 140.94,145.28 v140.55,145.67 | v123.23,142.52 v140.55,142.52
  Bottom 0.406: 6B.2 6B.3 | 1A.1 94.88,167.32 93.31,165.75 93.31,159.06 94.88,157.48 1A.5 95.28,157.48 97.24,155.51 97.24,135.83 v97.64,135.43 | v201.18,145.67 v201.18,126.77 | v140.55,142.52 v140.55,145.67 | v123.23,142.52 123.23,132.28 2B.14
COLUMNLATCH  (via drill 0.35)
  Top 0.406: v189.37,159.84 196.85,159.84 6A.4 | v189.37,50 188.98,50.39 185.83,50.39 185.43,50.79 166.93,50.79 v166.14,50 | v166.14,35.43 89.76,35.43 89.37,35.04 v84.25,35.04 | v84.25,10.24 83.86,10.63 37.8,10.63 7.87,40.55 7.87,49.21 9.84,49.21 J3.7
  Bottom 0.406: v189.37,50 v189.37,159.84 | v166.14,50 166.53,49.61 166.53,35.83 v166.14,35.43 | v84.25,10.24 v84.25,35.04
DISPLAYENABLE  (via drill 0.35)
  Top 0.406: v39.37,151.57 90.55,151.57 91.34,150.79 101.18,150.79 102.76,152.36 1A.8 | v39.37,70.47 23.23,70.47 10.24,57.48 J3.1
  Bottom 0.406: v39.37,70.47 v39.37,151.57
DOTCLOCK  (via drill 0.35)
  Top 0.406: v20.47,161.02 93.7,161.02 94.88,162.2 1A.3 | v20.47,89.37 18.5,87.4 v14.57,87.4
  Bottom 0.406: v20.47,89.37 v20.47,161.02 | v14.57,87.4 14.57,65.75 7.87,59.05 7.87,49.21 9.84,47.24 J3.9
DUE_3.3
  Bottom 0.406: J2.4 62.99,144.09 62.99,141.73 J2.3 62.99,141.34 74.02,130.31 74.02,85.83 81.1,78.74 B1.3.3V
DUE_5  (via drill 0.35)
  Top 0.406: v64.96,52.36 51.97,52.36 51.97,49.61 53.15,48.42 J1.2
  Bottom 0.406: v64.96,52.36 64.96,137.01 60.63,141.34 J2.5 60.63,141.73 60.63,144.09 J2.6
FRAMEA_BRIGHTNESS
  Bottom 0.406: 6E.12 204.33,20.47 201.18,23.62 201.18,79.53 204.33,82.68 6C.10
FRAMEB_BRIGHTNESS
  Bottom 0.406: 6E.6 196.85,12.99 200.39,12.99 200.39,81.5 204.33,85.43 6C.11
FRAMEC_BRIGHTNESS  (via drill 0.35)
  Top 0.406: v190.55,8.66 203.15,8.66 204.33,9.84 6E.8 | v190.55,79.13 190.94,78.74 198.03,78.74 202.36,83.07 202.36,87.4 204.33,87.4 6C.12
  Bottom 0.406: v190.55,8.66 190.55,46.46 190.94,46.85 190.94,78.74 v190.55,79.13
GND  (via drill 0.35)
  Top 0.406: 4E.15 164.17,24.02 175.59,24.02 176.38,23.23 5E.2 | 5C.15 184.25,95.28 186.61,97.64 v192.91,97.64 196.85,97.64 6C.1 | 1D.10 102.76,51.18 101.97,51.97 96.85,51.97 95.67,53.15 95.28,53.15 1D.4 | 1D.13 102.76,58.66 101.97,59.45 96.85,59.45 95.67,60.63 95.28,60.63 1D.1 | 1C.10 102.76,86.61 101.97,87.4 96.85,87.4 95.67,88.58 95.28,88.58 1C.4 | 1C.13 100.39,96.46 95.28,96.46 1C.1 | v152.36,95.28 143.7,95.28 3C.15 | v151.97,133.86 151.57,133.46 146.06,133.46 143.7,131.1 3B.15 | v151.97,166.53 143.7,166.53 3A.15 | v172.44,59.84 164.17,59.84 4D.15 | v172.44,95.28 164.17,95.28 4C.15 | v151.97,57.09 143.7,57.09 3D.14 | D3.K 22.05,44.09 12.99,44.09 J3.12 | D5.K 22.84,74.8 22.44,74.41 11.81,74.41 X2.4 | S1.2 80.31,127.56 83.07,124.8 94.88,124.8 1B.4 | 1B.10 102.76,121.65 101.97,120.87 99.21,120.87 95.28,116.93 1B.7
  Top 1.016: v213.36,116.84 208.28,121.92 6B.10 | 4A.10 v172.72,157.48 | 5E.10 v193.04,15.24
  Bottom 0.406: J3.2 J3.4 J3.6 J3.8 J3.10 J3.12 J3.14 J3.13 3.81,41.91 | 6C.15 204.33,95.28 202.36,97.24 202.36,120.08 204.33,122.05 6B.10 | 5E.2 176.77,22.84 176.77,20.47 5E.3 176.38,20.47 172.72,20.47 | 1B.10 102.76,122.05 100.79,124.02 100.79,127.56 102.76,129.53 1B.13 | S1.1 80.31,121.26 80.31,127.56 S1.2 | 3D.14 143.7,57.48 143.7,59.45 3D.15 | 91.44,17.72 94.88,17.72 1E.4 | 91.44,25.59 94.88,25.59 1E.1 | 91.44,53.54 94.88,53.54 1D.4 | 91.44,61.02 94.88,61.02 1D.1 | 91.44,88.98 94.88,88.98 1C.4 | 95.28,106.68 95.28,96.85 1C.1 | 91.44,124.41 94.88,124.41 1B.4 | 91.44,132.28 94.88,132.28 1B.1 | 1E.10 105.12,12.99 105.12,3.81 | 133.86,44.45 133.86,48.42 135.04,48.42 135.83,49.21 3D.6 | v152.36,95.28 152.4,95.28 | v151.97,133.86 152.4,133.86 | v151.97,166.53 152.4,166.53 | v172.44,59.84 172.72,59.84 | v172.44,95.28 172.72,95.28 | v151.97,57.09 152.4,57.09 | D4.K 25.2,37.8 22.44,40.55 22.44,43.7 D3.K | v192.91,97.64 193.04,97.64 | 213.38,45.72 213.38,44.88 213.36,44.45
  Bottom 1.016: 91.44,173.99 91.44,152.4 | 91.44,152.4 91.44,132.28 91.44,124.41 91.44,116.84 | 91.44,116.84 91.44,106.68 | 91.44,106.68 91.44,88.98 91.44,81.28 | 91.44,81.28 91.44,73.66 | 91.44,73.66 91.44,61.02 91.44,53.54 91.44,45.72 | 91.44,45.72 91.44,25.59 91.44,17.72 91.44,3.81 | 213.36,3.81 213.36,8.89 | 213.36,8.89 213.36,44.45 | 213.36,81.28 213.36,45.72 213.38,45.72 7D.7 | 213.36,81.28 213.36,106.68 | 213.36,106.68 v213.36,116.84 7B.7 | 129.54,173.99 129.54,151.13 | 129.54,151.13 129.54,148.59 | 129.54,106.68 129.54,115.57 | 129.54,115.57 129.54,121.92 | 129.54,121.92 129.54,148.59 | 129.54,106.68 129.54,86.36 | 129.54,86.36 129.54,80.01 | 129.54,80.01 129.54,71.12 | 129.54,71.12 129.54,50.8 | 129.54,50.8 129.54,44.45 | 129.54,44.45 129.54,15.24 | 129.54,15.24 129.54,3.81 | 152.4,3.81 152.4,44.45 | 152.4,44.45 152.4,57.09 152.4,71.12 | 152.4,71.12 152.4,80.01 | 152.4,80.01 152.4,95.28 152.4,113.03 | 152.4,113.03 152.4,133.86 152.4,166.53 152.4,173.99 | 152.4,71.12 C6.2 | C4.2 129.54,71.12 | C3.2 95.28,106.68 91.44,106.68 | 129.54,106.68 C5.2 | 172.72,173.99 v172.72,157.48 172.72,151.13 | 172.72,151.13 172.72,116.84 | 172.72,116.84 172.72,106.68 | 172.72,106.68 172.72,95.28 172.72,80.01 | 172.72,80.01 172.72,59.84 172.72,41.91 | 172.72,41.91 172.72,20.47 172.72,3.81 | 172.72,106.68 C7.2 | 193.04,173.99 193.04,152.4 | 193.04,152.4 193.04,97.64 193.04,80.01 | 193.04,80.01 193.04,71.12 | 193.04,71.12 193.04,45.72 | 193.04,45.72 v193.04,15.24 193.04,10.16 | 193.04,10.16 193.04,3.81 | 193.04,71.12 C8.2 | 129.54,148.59 119.38,148.59 2A.7 | 213.36,106.68 C9.2 | D1.K 21.59,173.99 | D2.K 29.21,173.99 | 38.1,173.99 D6.K 47.62,158.12 J2.16 J2.15
  Bottom 1.016: J2.1 J2.2 65.41,173.35 66.04,173.99 | B1.GND@1 B1.GND@0 91.44,73.66 | J1.6 76.2,30.48 B1.GND@2 | 3.81,88.9 16.51,88.9 17.53,87.88 B1.GND@4 | 91.44,152.4 1A.7 | 91.44,116.84 1B.7 | 91.44,81.28 1C.7 | 91.44,45.72 1D.7 | 95.25,3.81 1E.7 | 2E.10 129.54,15.24 | 3A.8 129.54,151.13 | 3B.8 129.54,115.57 | 3C.8 129.54,80.01 | 3D.8 133.86,44.45 129.54,44.45 | 4E.8 156.21,3.81 | 4D.8 152.4,44.45 | 152.4,113.03 4B.10 | 172.72,151.13 5A.8 | 172.72,116.84 5B.7 | 172.72,80.01 5C.8 | 5D.10 172.72,41.91 | 6E.7 193.04,10.16 | 6D.7 193.04,45.72 | 6C.8 193.04,80.01 | 6A.7 193.04,152.4 | 7C.7 213.36,81.28 | 7E.7 215.9,8.89 213.36,8.89 | 2D.10 129.54,50.8 | 2C.10 129.54,86.36 | 2B.10 129.54,121.92 | 4C.8 152.4,80.01
  Bottom 2.032: B1.GND@2 B1.GND@3 76.2,3.81
  Bottom 2.54: X1.5 11.43,125.73 X1.6 | X2.3 11.43,76.2 X2.4
  Bottom 5.08: 11.43,125.73 5.08,125.73 3.81,124.46 | 3.81,76.2 3.81,41.91 3.81,17.78 17.78,3.81 76.2,3.81 91.44,3.81 95.25,3.81 105.12,3.81 129.54,3.81 152.4,3.81 156.21,3.81 172.72,3.81 193.04,3.81 213.36,3.81 226.06,3.81 237.49,15.24 237.49,162.56 226.06,173.99 193.04,173.99 172.72,173.99 152.4,173.99 129.54,173.99 91.44,173.99 66.04,173.99 38.1,173.99 29.21,173.99 21.59,173.99 17.78,173.99 3.81,160.02 3.81,124.46 | 11.43,76.2 3.81,76.2 | 3.81,124.46 3.81,118.87 3.81,107.27 3.81,88.9 3.81,76.2
HRESET  (via drill 0.35)
  Top 0.406: v191.73,164.96 196.85,164.96 6A.2 | v191.73,148.03 191.34,147.64 170.47,147.64 169.29,146.46 v159.84,146.46 141.34,146.46 140.55,147.24 v126.77,147.24 | v123.23,67.72 122.44,68.5 106.69,68.5 98.82,76.38 98.82,78.74 100,78.74 101.18,79.92 103.94,79.92 115.35,91.34 2C.3 | v110.63,120.47 110.63,122.05 115.35,126.77 2B.3 115.75,126.77 v120.87,126.77
  Bottom 0.406: 156.3,162.6 156.3,164.96 4A.2 | v191.73,148.03 v191.73,164.96 | v159.84,146.46 159.84,159.06 156.3,162.6 | 156.3,162.6 4A.3 | 2B.3 115.75,127.17 115.75,129.53 2B.2 | 2C.3 115.75,91.73 115.75,93.7 2C.2 115.35,94.09 111.42,94.09 110.63,94.88 v110.63,120.47 | v123.23,67.72 123.23,61.02 2D.14 | v126.77,147.24 123.23,143.7 120.87,143.7 v120.87,126.77
I/O_0  (via drill 0.35)
  Top 0.406: v211.81,62.2 194.88,62.2 194.88,60.24 195.67,59.45 196.06,59.45 196.85,58.66 6D.2 | v171.26,109.06 v211.81,109.06 | v171.26,129.53 176.38,129.53 5B.2 | v79.92,24.02 69.69,24.02 66.14,20.47 B1.46 | v148.82,38.58 v83.07,38.58 | v148.82,29.13 149.21,28.74 172.05,28.74 173.23,27.56 v211.81,27.56
  Bottom 0.406: v211.81,109.06 212.2,108.66 212.2,62.6 v211.81,62.2 v211.81,27.56 | v171.26,129.53 v171.26,109.06 | v79.92,24.02 79.53,23.62 79.53,22.44 80.71,21.26 83.07,21.26 v83.07,38.58 | v148.82,29.13 v148.82,38.58
I/O_1  (via drill 0.35)
  Top 0.406: v233.86,34.65 233.46,35.04 v206.69,35.04 v180.31,35.04 | v233.86,135.04 227.56,135.04 227.16,135.43 197.64,135.43 189.37,127.17 184.25,127.17 5B.12 | v51.97,65.35 53.15,66.53 v88.98,66.53 | v88.98,36.22 165.35,36.22 166.93,37.8 v179.92,37.8
  Bottom 0.406: v206.69,35.04 206.69,53.54 204.72,55.51 6D.12 | v233.86,34.65 234.25,35.04 234.25,134.65 v233.86,135.04 | v51.97,65.35 51.97,47.64 64.57,35.04 64.57,24.41 68.5,20.47 B1.48 | v88.98,36.22 v88.98,66.53 | v179.92,37.8 180.31,37.4 v180.31,35.04
I/O_2  (via drill 0.35)
  Top 0.406: v206.69,72.44 v199.21,72.44 | v206.69,96.46 206.69,99.21 199.21,99.21 198.03,100.39 v196.85,100.39 | v196.85,114.17 176.38,114.17 174.41,116.14 174.41,121.65 176.38,121.65 5B.5 | v77.56,22.84 73.62,22.84 71.26,20.47 B1.50 | v85.43,33.07 85.83,33.47 95.67,33.47 96.06,33.86 157.48,33.86 158.27,34.65 165.35,34.65 165.75,34.25 167.72,34.25 169.69,36.22 v177.56,36.22 | v198.82,30.32 v177.56,30.32
  Bottom 0.406: 198.82,51.97 199.61,51.97 199.61,72.05 v199.21,72.44 | 198.82,51.97 197.64,51.97 196.85,51.18 6D.5 | v206.69,96.46 v206.69,72.44 | v196.85,114.17 v196.85,100.39 | v77.56,22.84 77.95,22.44 77.95,14.96 83.86,9.05 85.43,9.05 v85.43,33.07 | v177.56,30.32 v177.56,36.22 | 198.82,51.97 v198.82,30.32
I/O_3  (via drill 0.35)
  Top 0.406: v231.1,112.6 204.33,112.6 198.82,118.11 185.43,118.11 184.25,119.29 5B.9 | v231.1,38.98 v202.36,38.98 182.68,38.98 178.74,35.04 v171.26,35.04 | v171.26,22.84 162.6,22.84 161.42,24.02 160.63,24.02 159.45,22.84 146.46,22.84 142.52,26.77 114.17,26.77 113.39,25.98 112.2,25.98 111.42,26.77 94.09,26.77 88.58,21.26 80.71,21.26 79.92,22.05 78.74,22.05 78.35,21.65 77.17,21.65 76.77,22.05 75.59,22.05 74.02,20.47 B1.52
  Bottom 0.406: v231.1,38.98 v231.1,112.6 | v202.36,38.98 202.36,46.06 204.33,48.03 6D.9 | v171.26,35.04 v171.26,22.84
INTENSITYCOUNTA  (via drill 0.35)
  Top 0.406: 7C.9 224.8,83.86 226.77,85.83 226.77,90.16 218.5,90.16 217.32,91.34 7C.3 216.93,91.73 216.14,92.52 204.72,92.52 6C.14 204.33,92.91 198.03,99.21 195.28,99.21 v194.49,100 | v106.3,162.2 103.15,162.2 1A.12 | v106.3,140.16 106.69,140.55 152.36,140.55 153.94,138.98 163.39,138.98 166.14,136.22 v194.49,136.22
  Bottom 0.406: v106.3,140.16 v106.3,162.2 | v194.49,100 v194.49,136.22
INTENSITYCOUNTB  (via drill 0.35)
  Top 0.406: v198.82,104.33 212.6,104.33 v214.96,101.97 | v105.12,141.34 153.15,141.34 153.54,141.73 164.96,141.73 v165.35,141.34 | v200,138.98 v165.35,138.98
  Bottom 0.406: v198.82,104.33 198.82,103.94 | 198.82,103.94 198.82,97.24 196.85,95.28 6C.2 | v214.96,101.97 214.96,88.58 216.93,86.61 7C.5 | v105.12,141.34 105.12,162.99 103.15,164.96 1A.13 | v165.35,138.98 v165.35,141.34 | v200,138.98 200.39,138.58 200.39,134.65 200,134.25 200,106.69 200.39,106.3 200.39,105.51 198.82,103.94
LEDPIN
  Top 0.406: R7.1 25.59,85.04 32.68,85.04 B1.13
LSA0  (via drill 0.35)
  Top 0.406: v90.16,127.17 94.88,127.17 1B.3 | v111.02,148.82 v101.18,148.82 v90.16,148.82 | v125.98,166.53 135.83,166.53 3A.2 | v100.79,77.95 110.24,77.95 111.02,77.17 133.46,77.17 134.25,77.95 151.97,77.95 151.97,90.94 155.91,94.88 4C.2
  Bottom 0.406: v90.16,148.82 v90.16,127.17 | v111.02,148.82 111.81,149.61 111.81,166.53 115.75,170.47 125.98,170.47 v125.98,166.53 | v100.79,77.95 100.79,105.51 100,106.3 100,112.2 100.79,112.99 100.79,122.83 100,123.62 100,133.46 101.18,134.65 v101.18,148.82
LSA1  (via drill 0.35)
  Top 0.406: v111.42,124.8 103.15,124.8 1B.11 | v111.42,146.46 113.39,148.43 118.5,148.43 | 118.5,148.43 121.65,148.43 125.59,152.36 v126.38,152.36 | v126.38,158.66 135.83,158.66 3A.5 | v142.91,76.77 152.76,76.77 152.76,84.25 155.91,87.4 4C.5 | v140.16,66.14 126.38,66.14 125.98,65.75 v118.5,65.75 | 118.5,148.43 v118.5,147.64
  Bottom 0.406: v111.42,146.46 v111.42,124.8 | v126.38,158.66 v126.38,152.36 | v142.91,76.77 142.91,68.11 140.94,66.14 v140.16,66.14 | v118.5,147.64 v118.5,65.75
LSA2  (via drill 0.35)
  Top 0.406: v137.79,144.88 94.88,144.88 94.88,136.61 97.24,134.25 97.24,121.26 96.46,120.47 96.06,120.47 95.28,119.69 1B.6 | v138.58,155.91 143.31,155.91 3A.11 | v161.81,110.63 161.02,111.42 147.24,111.42 145.28,113.39 135.43,113.39 133.86,114.96 v133.86,116.93
  Bottom 0.406: v138.58,155.91 138.58,145.67 v137.79,144.88 136.61,143.7 136.61,138.19 133.86,135.43 v133.86,116.93 | v161.81,110.63 161.81,86.22 162.99,86.22 163.78,85.43 4C.11
LSA3  (via drill 0.35)
  Top 0.406: v116.14,115.35 104.33,115.35 103.15,116.53 1B.8 | v116.14,105.12 v150,105.12 170.08,105.12 v171.26,103.94 | v171.26,92.91 164.17,92.91 4C.14 | v148.82,163.78 143.7,163.78 3A.14
  Bottom 0.406: v116.14,105.12 v116.14,115.35 | v171.26,92.91 v171.26,103.94 | v148.82,163.78 148.82,137.4 150,136.22 150,135.43 149.61,135.04 149.61,124.02 150,123.62 150,121.26 149.61,120.87 149.61,118.9 150,118.5 v150,105.12
LSA4  (via drill 0.35)
  Top 0.406: v98.82,64.96 99.21,64.57 114.57,64.57 115.35,63.78 147.24,63.78 151.18,59.84 155.91,59.84 4D.2 | v125.2,131.1 135.83,131.1 3B.2 | v96.06,138.58 v125.2,138.58
  Bottom 0.406: 98.03,91.34 98.42,91.34 98.42,65.35 v98.82,64.96 | 98.03,91.34 95.28,91.34 1C.3 | v125.2,138.58 v125.2,131.1 | v96.06,138.58 96.46,138.19 96.46,133.46 97.64,132.28 97.64,107.48 98.03,107.09 98.03,91.34
LSA5  (via drill 0.35)
  Top 0.406: v127.17,98.03 106.69,98.03 106.69,92.52 103.15,88.98 1C.11 | v127.17,119.29 131.89,119.29 135.43,122.83 135.83,122.83 3B.5 | v145.67,53.15 155.12,53.15 155.91,52.36 4D.5 | v107.87,37.4 v145.67,37.4 | v107.87,59.45 106.3,61.02 v106.3,62.6
  Bottom 0.406: v127.17,119.29 v127.17,98.03 | v145.67,37.4 v145.67,53.15 | v107.87,59.45 v107.87,37.4 | v106.3,62.6 105.12,63.78 105.12,86.61 103.15,88.58 1C.11
LSA6  (via drill 0.35)
  Top 0.406: v99.61,83.86 95.28,83.86 1C.6 94.88,83.46 90.16,83.46 v90.16,72.05 | v145.28,109.45 v98.82,109.45 | v161.02,32.28 160.63,31.89 97.24,31.89 96.85,31.5 v90.16,31.5
  Bottom 0.406: v99.61,83.86 99.21,84.25 99.21,109.06 v98.82,109.45 | v145.28,109.45 145.67,109.84 145.67,118.5 143.7,120.47 3B.11 | v161.02,32.28 161.02,33.86 161.42,34.25 161.42,38.19 161.02,38.58 161.02,48.42 162.99,48.42 163.78,49.21 4D.11 | v90.16,72.05 v90.16,31.5
LSA7  (via drill 0.35)
  Top 0.406: v103.15,66.93 122.44,66.93 122.83,66.53 123.62,66.53 125.2,68.11 v141.34,68.11 146.06,68.11 147.24,66.93 v162.2,66.93 | v141.34,126.38 141.73,126.38 143.31,127.95 3B.14
  Bottom 0.406: v103.15,66.93 103.15,81.1 1C.8 | v162.2,66.93 161.81,66.53 161.81,59.05 163.78,57.09 4D.14 | v141.34,126.38 140.94,125.98 140.94,85.43 141.34,85.04 141.34,84.25 140.55,83.46 140.55,68.9 v141.34,68.11
LSA8  (via drill 0.35)
  Top 0.406: v98.42,55.51 95.28,55.51 1D.3 | v96.46,32.68 96.85,33.07 v158.27,33.07 | v119.69,99.61 131.5,99.61 135.83,95.28 3C.2 | v98.42,40.16 v120.87,40.16
  Bottom 0.406: v98.42,55.51 98.03,55.12 98.03,40.16 | 98.03,40.16 98.03,34.25 v96.46,32.68 | v158.27,33.07 158.27,25.98 156.3,24.02 4E.2 | v119.69,99.61 119.29,99.21 119.29,66.53 120.87,64.96 v120.87,40.16 | 98.03,40.16 v98.42,40.16
LSA9  (via drill 0.35)
  Top 0.406: v131.1,16.54 155.91,16.54 4E.5 | v106.3,42.91 v131.1,42.91 | v133.46,78.74 133.46,85.43 134.65,86.61 135.04,86.61 135.83,87.4 3C.5 | v133.46,74.8 133.07,75.2 128.35,75.2 127.95,75.59 v101.18,75.59
  Bottom 0.406: v131.1,42.91 v131.1,16.54 | v106.3,42.91 106.3,50 103.15,53.15 1D.11 102.76,53.54 100.79,55.51 100.79,75.2 v101.18,75.59 | v133.46,74.8 v133.46,78.74
LSA10  (via drill 0.35)
  Top 0.406: v100,48.42 95.28,48.42 1D.6 | v100,76.77 110.24,76.77 110.63,76.38 v141.73,76.38 | v169.29,65.35 168.9,64.96 152.36,64.96 151.18,63.78 v148.82,63.78 | v148.82,85.04 143.7,85.04 3C.11
  Bottom 0.406: v100,76.77 v100,48.42 | v141.73,76.38 141.34,76.77 141.34,83.07 143.31,85.04 3C.11 | v169.29,65.35 168.9,64.96 168.9,7.48 167.32,7.48 166.53,8.27 166.53,11.42 164.17,13.78 4E.11 | v148.82,85.04 v148.82,63.78
LSA11  (via drill 0.35)
  Top 0.406: v112.6,45.67 103.15,45.67 1D.8 | v112.6,27.16 112.99,27.56 142.91,27.56 143.7,26.77 v148.82,26.77 v153.94,26.77 | v150,92.91 143.7,92.91 3C.14
  Bottom 0.406: v112.6,27.16 v112.6,45.67 | v153.94,26.77 153.94,23.62 154.72,22.84 159.84,22.84 159.84,22.44 160.63,21.65 163.78,21.65 4E.14 | v150,92.91 150,80.71 149.61,80.31 149.61,64.57 150,64.17 150,52.76 149.61,52.36 149.61,51.58 151.18,50 151.18,12.21 150.39,11.42 148.82,11.42 v148.82,26.77
LSCHIPENABLE  (via drill 0.35)
  Top 0.406: v99.61,43.31 100.39,44.09 127.17,44.09 129.92,46.85 129.92,51.58 135.43,51.58 135.83,51.97 3D.5
  Bottom 0.406: v99.61,43.31 99.61,21.26 96.06,21.26 95.28,20.47 1E.3 | 3D.13 143.31,54.33 139.76,54.33 137.79,52.36 136.22,52.36 3D.5
LSWHICHBUFFER  (via drill 0.35)
  Top 0.406: 5B.13 183.86,129.92 181.89,131.89 176.77,131.89 5B.1 | v105.12,49.61 107.87,52.36 v113.39,52.36 | v113.39,62.6 135.83,62.6 3D.1 | v112.6,134.65 112.99,134.25 135.04,134.25 135.83,133.46 3B.1 | v170.08,124.41 176.38,124.41 5B.4 | v170.08,74.41 159.06,74.41 158.66,74.8 143.31,74.8 142.52,74.02 v138.58,74.02
  Bottom 0.406: 5B.10 184.25,122.05 186.22,124.02 186.22,127.56 184.25,129.53 5B.13 | 5B.4 176.77,124.8 178.74,126.77 178.74,129.92 176.77,131.89 5B.1 | v105.12,49.61 105.12,45.28 100.79,40.95 100.79,12.21 102.76,10.24 1E.8 | v113.39,62.6 v113.39,52.36 | 138.58,95.28 136.22,97.64 3C.1 | 138.58,95.28 v138.58,74.02 137.01,72.44 137.01,63.39 136.22,62.6 3D.1 | 137.4,131.89 138.98,130.31 138.98,118.9 139.37,118.5 139.37,96.06 138.58,95.28 | 137.4,131.89 136.22,133.07 3B.1 | v112.6,134.65 112.6,164.57 115.35,167.32 2A.1 | 137.4,131.89 137.4,142.91 139.37,144.88 139.37,146.06 140.16,146.85 140.16,164.96 136.22,168.9 3A.1 | v170.08,124.41 170.08,83.46 170.47,83.07 170.47,74.8 v170.08,74.41
LSWRITE  (via drill 0.35)
  Top 0.406: v97.24,8.66 107.09,8.66 109.84,11.42 v141.34,11.42
  Bottom 0.406: v97.24,8.66 97.24,10.63 95.28,12.6 1E.6 | 141.34,44.88 v141.34,11.42 | 141.34,44.88 143.31,46.85 3D.10 | 141.34,44.88 141.34,50.79 134.65,50.79 133.86,51.58 133.86,58.66 135.04,58.66 135.83,59.45 3D.2
MEM_A_0  (via drill 0.35)
  Top 0.406: v181.1,120.08 178.74,122.44 178.74,126.77 176.77,126.77 5B.3 176.38,126.77 167.72,126.77 164.17,123.23 4B.15
  Bottom 0.406: v181.1,120.08 181.1,99.61 176.77,95.28 5C.2
MEM_A_1  (via drill 0.35)
  Top 0.406: v174.41,122.83 166.14,122.83 164.17,120.87 4B.14
  Bottom 0.406: 178.74,118.11 178.74,119.29 183.86,124.41 5B.11 | 178.74,118.11 178.74,111.02 179.13,110.63 179.13,105.91 174.41,101.18 174.41,89.76 176.38,87.8 5C.5 | v174.41,122.83 174.41,118.9 175.2,118.11 178.74,118.11
MEM_A_2  (via drill 0.35)
  Top 0.406: v179.92,111.42 162.99,111.42 162.6,111.81 161.81,111.81 161.81,116.14 163.78,118.11 4B.13 | v179.92,118.9 179.53,119.29 176.77,119.29 5B.6 | v179.53,99.61 179.53,89.76 183.86,85.43 5C.11
  Bottom 0.406: v179.92,118.9 v179.92,111.42 179.92,100 v179.53,99.61
MEM_A_3  (via drill 0.35)
  Top 0.406: v194.49,92.91 184.25,92.91 5C.14 | 5B.8 184.25,116.53 194.49,116.53 v195.67,115.35 198.03,115.35 198.03,113.78 197.24,112.99 166.53,112.99 164.17,115.35 4B.12
  Bottom 0.406: v194.49,92.91 194.88,93.31 194.88,98.82 195.67,99.61 v195.67,115.35
MEM_B_0
  Top 0.406: 5D.15 184.25,52.36 185.04,53.15 194.09,53.15 196.46,55.51 196.85,55.51 6D.3
  Bottom 0.406: 5C.3 176.77,92.52 179.92,89.37 179.92,47.64 180.71,46.85 181.89,46.85 181.89,47.24 182.28,47.64 182.28,48.82 181.89,49.21 181.89,50 183.86,51.97 5D.15
MEM_B_1  (via drill 0.35)
  Top 0.406: 5D.14 184.25,49.21 185.04,48.42 187.01,48.42 191.34,44.09 198.03,44.09 202.36,48.42 202.36,53.15 204.33,53.15 6D.11 204.72,53.54 v214.96,53.54 | v214.96,70.08 213.38,70.08 205.51,77.95 181.1,77.95 181.1,80.71 176.77,85.04 5C.6
  Bottom 0.406: v214.96,53.54 v214.96,70.08
MEM_B_2  (via drill 0.35)
  Top 0.406: v186.22,51.58 186.61,51.18 193.7,51.18 196.46,48.42 196.85,48.42 6D.6 | v186.22,63.39 v186.22,66.14
  Bottom 0.406: 5D.13 184.25,47.24 185.04,48.03 186.22,48.03 v186.22,51.58 v186.22,63.39 | v186.22,66.14 186.22,81.5 185.04,81.5 184.25,82.28 5C.10
MEM_B_3  (via drill 0.35)
  Top 0.406: 5D.12 184.25,44.09 185.04,43.31 201.97,43.31 204.33,45.67 6D.8 204.72,46.06 v210.63,46.06 | v211.02,101.18 210.63,101.58 181.89,101.58 181.89,92.52 183.86,90.55 5C.13
  Bottom 0.406: v211.02,101.18 211.02,62.99 210.63,62.6 v210.63,46.06
N$1
  Top 0.406: Q1.1 222.05,167.72 214.96,167.72 R1.1 214.57,167.32 206.69,167.32 6A.13
N$2
  Top 0.406: 6A.5 201.57,162.2 204.33,162.2 6A.12 204.72,162.2 212.6,162.2 214.57,160.24 R1.2
  Bottom 0.406: C1.2 214.57,157.48 214.57,159.84 R1.2
N$3
  Top 0.406: R2.1 216.93,152.36 214.96,152.36 C1.1 214.57,152.76 211.81,152.76 204.72,159.84 6A.11
N$4
  Bottom 0.406: Q1.2 222.44,162.2 223.23,161.42 223.23,156.3 C2.2
N$5
  Top 0.406: 221.65,152.76 218.5,155.91 C2.1 | 221.65,152.76 224.41,152.76 R2.2 | 221.65,152.76 219.69,150.79 211.42,150.79 204.72,157.48 6A.10
N$6  (via drill 0.35)
  Top 0.406: v107.87,159.84 103.15,159.84 1A.11 | v107.87,147.64 111.42,147.64 112.99,149.21 118.11,149.21 121.26,152.36 121.26,159.84 122.83,159.84 2A.11
  Bottom 0.406: v107.87,147.64 v107.87,159.84
N$7  (via drill 0.35)
  Top 0.406: 199.61,131.89 204.33,127.17 6B.12 | 199.61,131.89 196.85,131.89 6B.1 | v226.77,134.25 201.97,134.25 199.61,131.89
  Bottom 0.406: v226.77,134.25 226.77,120.47 225.59,120.47 224.8,119.69 7B.9
N$8
  Top 0.406: 6B.9 204.72,119.29 208.27,115.75 214.17,115.75 214.96,116.53 214.96,118.11 220.87,118.11 224.41,121.65 7B.10
N$9  (via drill 0.35)
  Top 0.406: v204.72,113.78 205.12,114.17 224.8,114.17 226.77,116.14 226.77,126.77 224.8,126.77 7B.12
  Bottom 0.406: v204.72,113.78 204.72,116.53 6B.8
N$10
  Top 0.406: 7B.13 220.87,133.46 213.38,133.46 204.72,124.8 6B.11
N$11
  Bottom 0.406: 7D.1 217.32,61.02 220.47,64.17 220.47,128.74 217.32,131.89 7B.1
N$12  (via drill 0.35)
  Top 0.406: v222.05,129.53 217.32,129.53 7B.2
  Bottom 0.406: v222.05,129.53 222.05,58.27 217.32,53.54 7D.4
N$13  (via drill 0.35)
  Top 0.406: v214.96,149.61 207.48,149.61 204.72,152.36 6A.8
  Bottom 0.406: v214.96,149.61 214.96,126.77 216.93,124.8 7B.4
N$14  (via drill 0.35)
  Top 0.406: v87.01,154.72 94.88,154.72 1A.6 | v155.12,101.58 v87.01,101.58 | v166.14,108.27 v155.12,108.27 | v174.01,128.35 v166.14,128.35 | v163.78,144.49 v174.01,144.49
  Bottom 0.406: v87.01,101.58 v87.01,154.72 | v155.12,108.27 v155.12,101.58 | v166.14,128.35 v166.14,108.27 | v174.01,144.49 v174.01,128.35 | v163.78,144.49 163.78,150 161.81,151.97 161.81,165.75 163.78,167.72 4A.14
N$15  (via drill 0.35)
  Top 0.406: 4A.1 156.3,167.32 157.09,166.53 159.84,166.53 163.78,162.6 4A.12 164.17,162.2 v174.01,162.2 | v178.74,166.53 183.86,166.53 5A.15
  Bottom 0.406: v178.74,166.53 178.74,169.29 177.56,170.47 174.01,170.47 v174.01,162.2
N$17  (via drill 0.35)
  Top 0.406: v174.41,155.12 164.17,155.12 4A.9
  Bottom 0.406: v174.41,155.12 174.41,156.69 175.2,157.48 179.53,157.48 179.53,159.45 183.86,163.78 5A.14
N$18
  Top 0.406: 4A.8 164.17,152.36 172.83,152.36 175.59,149.61 177.56,149.61 181.89,153.94 181.89,161.02 183.86,161.02 5A.13
N$19  (via drill 0.35)
  Top 0.406: v180.71,157.48 175.2,157.48 174.01,158.66 165.35,158.66 164.17,159.84 4A.11
  Bottom 0.406: v180.71,157.48 181.89,158.66 183.86,158.66 5A.12
N$20  (via drill 0.35)
  Top 0.406: v189.37,167.72 196.85,167.72 6A.1
  Bottom 0.406: v189.37,167.72 189.37,170.47 183.07,170.47 181.89,169.29 181.89,164.17 176.77,159.06 5A.5
N$21
  Top 0.406: 6A.3 196.85,162.6 195.67,163.78 191.34,163.78 186.22,168.9 186.22,170.47 180.71,170.47 176.77,166.53 5A.2
N$22
  Bottom 0.406: 7D.10 224.8,51.18 224.8,53.15 7D.11
N$23  (via drill 0.35)
  Top 0.406: v133.07,157.48 2A.10 | v138.98,157.48 145.67,157.48 152.36,150.79 165.75,150.79 v166.14,151.18 | v166.14,137.79 166.53,137.4 v199.21,137.4 | v199.21,105.91 199.61,105.51 212.99,105.51 224.41,94.09 7C.13
  Bottom 0.406: 7C.10 224.41,86.61 222.83,88.19 222.83,92.13 224.41,93.7 7C.13 | v138.98,157.48 v133.07,157.48 | v166.14,151.18 166.53,150.79 166.53,138.19 v166.14,137.79 | v199.21,105.91 v199.21,137.4
N$24
  Bottom 1.016: R4.2 D2.A
N$25
  Top 0.406: 5C.12 184.25,87.8 188.19,91.73 196.06,91.73 196.85,92.52 6C.3
N$26
  Top 0.406: 5C.9 184.25,80.31 185.04,81.1 186.61,81.1 195.67,90.16 196.85,90.16 6C.4
N$27
  Bottom 0.406: R6.2 27.95,44.09 27.95,37.8 D4.A
N$28
  Bottom 0.406: R5.2 25.2,48.03 24.8,47.64 24.8,44.09 D3.A
N$29
  Bottom 1.016: D1.A R3.2
N$34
